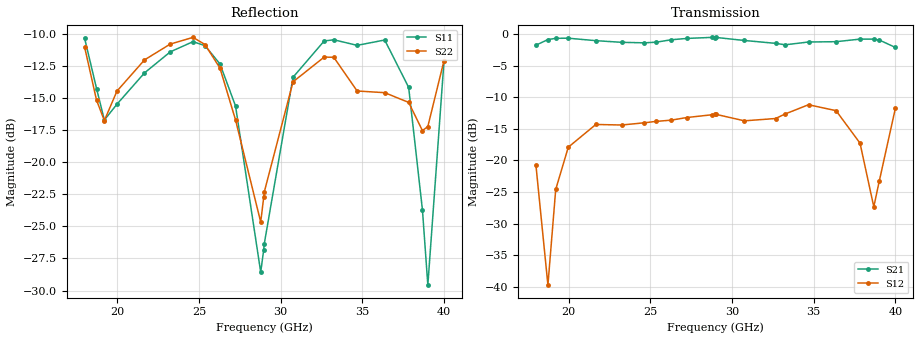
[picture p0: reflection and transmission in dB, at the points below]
! MS46524B
! 12345/M1: Not Set/M2: Not Set
! 3/11/2021 9:54:44 PM
! D:\WEBSITE FILES\DATASHEETS\MEASURED DATA\18.0 - 40.0 GHZ (D4I1840).S2P
! CHANNEL.1
! TR.MEASUREMENT
! RAW.DATA
# GHZ S RI R 50.0
! FREQ.GHZ  S11RE  S11IM  S21RE  S21IM  S12RE  S12IM  S22RE  S22IM
!; PortSelection: Port_12
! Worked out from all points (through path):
!   601 points, 18 GHz to 40 GHz, reference 50 ohm
!   highest |S21| = -0.52 dB at 28.78 GHz (marker M1); lowest = -2.1 dB at 40 GHz (marker M2)
!   lowest |S11| = -29.6 dB at 39.01 GHz (marker M3), VSWR 1.07, Z = 49.5 + j3.26 ohm
!   |S11| at or under -10 dB: start of sweep to end of sweep
!   |S22| runs from -26.7 to -10.2 dB; largest |S21 - S12| = 0.92
!   S11 on the Smith chart (normalised r, x): 18 GHz: 1.08, -0.66; 24.64 GHz: 0.54, -0.01; 28.96 GHz: 0.98, -0.09; 33.25 GHz: 1.33, +0.65; 40 GHz: 1.54, -0.33
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18  0.1274 -0.2768  0.4634 -0.6732  -0.0782 0.048  0.0959 -0.2647
18.73333  0.0137 -0.1932  -0.1361 -0.8951  0.0103 -0.000586  0.0148 -0.1738
19.21  0.0234 -0.1443  -0.5463 -0.7476  -0.0135 -0.0574  0.0354 -0.141
19.98  0.0533 -0.1597  -0.9123 -0.1713  -0.1205 -0.0413  0.054 -0.1815
21.66667  -0.0455 -0.2183  -0.1826 0.8684  -0.00695 0.1926  -0.1066 -0.2268
23.24333  -0.1947 -0.1861  0.7923 0.3374  0.1871 0.0375  -0.2607 -0.1244
24.63667  -0.2951 -0.00659  0.6084 -0.5979  0.1128 -0.1636  -0.2935 0.0892
25.37  -0.2574 0.1218  0.1504 -0.8501  -0.00264 -0.2039  -0.2106 0.196
26.28667  -0.1146 0.2128  -0.5183 -0.7385  -0.1456 -0.1493  -0.0498 0.2275
27.24  0.037 0.1615  -0.9181 -0.1084  -0.2186 0.00668  0.0749 0.1256
28.78  0.0176 -0.0329  -0.2756 0.9008  -0.0404 0.2265  -0.0238 -0.0534
28.96333  -0.00669 -0.045  -0.1204 0.9312  -0.0016 0.2316  -0.0515 -0.0517
29  -0.0122 -0.0466  -0.0885 0.9373  0.00606 0.232  -0.0573 -0.0509
30.76  -0.1578 0.1454  0.8878 0.0704  0.2057 -0.00938  -0.0951 0.1826
32.66667  0.1088 0.2764  -0.0249 -0.8446  0.0161 -0.2142  0.1981 0.1638
33.25333  0.2034 0.2209  -0.4084 -0.7143  -0.0994 -0.2111  0.2474 0.0679
34.68333  0.2843 0.0269  -0.8447 0.191  -0.2653 0.0764  0.1517 -0.1137
36.37  0.181 -0.2388  0.1645 0.8553  0.1302 0.2109  -0.0133 -0.1863
37.83667  -0.1015 -0.1675  0.9123 -0.0172  0.1119 -0.0792  -0.1674 0.0355
38.68  -0.0651 -0.00406  0.5631 -0.7178  0.0349 -0.0251  -0.00627 0.1327
39.01  -0.00445 0.0329  0.269 -0.8574  0.0681 -0.00305  0.0766 0.1146
40  0.2262 -0.1018  -0.5553 -0.5543  0.1224 -0.2276  0.1719 -0.1801
